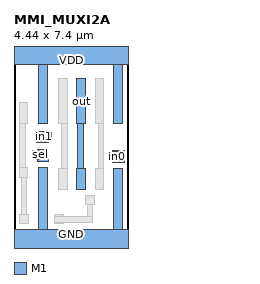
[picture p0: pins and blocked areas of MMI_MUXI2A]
MACRO MMI_MUXI2A
	CLASS CORE ;
	FOREIGN MMI_MUXI2A 0 0 ;
	SIZE 4.44 BY 7.4 ;
	SYMMETRY X Y ;
	SITE CORE1 ;
	PIN out
		DIRECTION output ;
		USE SIGNAL ;
		PORT
			LAYER M1 ;
			RECT 2.445 4.6 2.785 6.36 ;
			LAYER M1 ;
			RECT 2.47 2.87 2.7 4.6 ;
			LAYER M1 ;
			RECT 2.445 2.03 2.785 2.87 ;
		END
		AntennaDiffArea 1.4904 ;
	END out
	PIN sel
		DIRECTION input ;
		USE SIGNAL ;
		PORT
			LAYER M1 ;
			RECT 0.905 3.57 1.355 3.59 ;
			LAYER M1 ;
			RECT 0.705 3.23 1.355 3.57 ;
			LAYER M1 ;
			RECT 0.905 3.14 1.355 3.23 ;
		END
		AntennaGateArea 0.7452 ;
	END sel
	PIN in1
		DIRECTION input ;
		USE SIGNAL ;
		PORT
			LAYER M1 ;
			RECT 0.89 4.265 1.34 4.315 ;
			LAYER M1 ;
			RECT 0.89 3.925 1.46 4.265 ;
			LAYER M1 ;
			RECT 0.89 3.865 1.34 3.925 ;
		END
		AntennaGateArea 0.495 ;
	END in1
	PIN GND
		DIRECTION inout ;
		USE GROUND ;
		PORT
			LAYER M1 ;
			RECT 0.965 0.5 1.305 2.91 ;
			LAYER M1 ;
			RECT 3.885 0.5 4.225 2.87 ;
			LAYER M1 ;
			RECT 0 -0.5 4.44 0.5 ;
		END
	END GND
	PIN VDD
		DIRECTION inout ;
		USE POWER ;
		PORT
			LAYER M1 ;
			RECT 0 6.9 4.44 7.9 ;
			LAYER M1 ;
			RECT 0.965 4.6 1.305 6.9 ;
			LAYER M1 ;
			RECT 3.885 4.6 4.225 6.9 ;
		END
	END VDD
	PIN in0
		DIRECTION input ;
		USE SIGNAL ;
		PORT
			LAYER M1 ;
			RECT 3.845 3.51 4.295 3.565 ;
			LAYER M1 ;
			RECT 3.74 3.17 4.295 3.51 ;
			LAYER M1 ;
			RECT 3.845 3.115 4.295 3.17 ;
		END
		AntennaGateArea 0.4968 ;
	END in0
	OBS
		LAYER M1 ;
		RECT 0.205 4.6 0.545 5.44 ;
		LAYER M1 ;
		RECT 1.725 4.6 2.065 6.36 ;
		LAYER M1 ;
		RECT 3.165 4.6 3.505 6.36 ;
		LAYER M1 ;
		RECT 0.21 2.91 0.44 4.6 ;
		LAYER M1 ;
		RECT 0.205 2.53 0.545 2.91 ;
		LAYER M1 ;
		RECT 0.275 1.07 0.505 2.53 ;
		LAYER M1 ;
		RECT 0.225 0.73 0.565 1.07 ;
		LAYER M1 ;
		RECT 1.835 2.87 2.065 4.6 ;
		LAYER M1 ;
		RECT 3.275 2.87 3.505 4.6 ;
		LAYER M1 ;
		RECT 1.725 2.03 2.065 2.87 ;
		LAYER M1 ;
		RECT 3.165 2.03 3.505 2.87 ;
		LAYER M1 ;
		RECT 2.785 1.455 3.125 1.795 ;
		LAYER M1 ;
		RECT 1.58 0.995 1.92 1.07 ;
		LAYER M1 ;
		RECT 2.845 0.995 3.075 1.455 ;
		LAYER M1 ;
		RECT 1.58 0.765 3.075 0.995 ;
		LAYER M1 ;
		RECT 1.58 0.73 1.92 0.765 ;
	END
END MMI_MUXI2A
